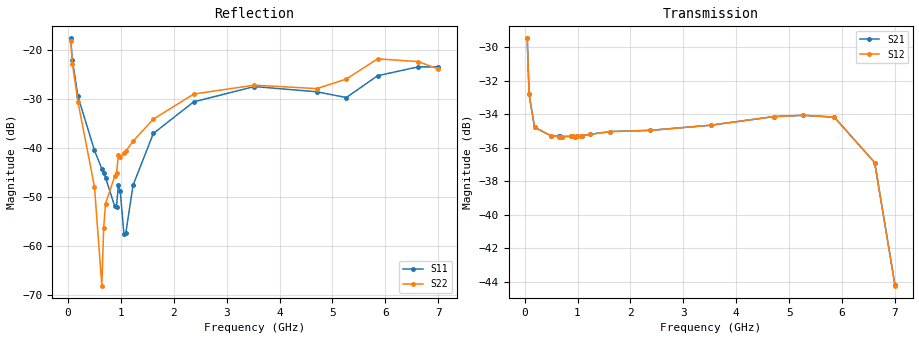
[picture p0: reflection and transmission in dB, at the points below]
! Integrated Device Technology
! Corporate Headquarters
! 6024 Silver Creek Valley Road
! San Jose, CA 95138  USA
! Phone:  1-408-284-8200
! Toll Free:  1-800-223-1366
! Webpage:  http://www.idt.com/
! Timing and RF Division
! 515 Groton Road, Suite 102
! Westford, MA 01886-6024
! Device:  F2258
! Description: Voltage Variable RF Attenuator
! Frequency:  50.0 -  6000.00 MHz
! Package:  3x3 mm Thin QFN Plastic Package: 16 pin
! Ports:  2 RF, 2 DC
!  Pin  1  = NC
!  Pin  2  = NC
!  Pin  3  = RF2  = Port 2
!  Pin  4  = GND
!  Pin  5  = Vdd
!  Pin  6  = NC
!  Pin  7  = VCTRL
!  Pin  8  = NC
!  Pin  9  = GND
!  Pin 10  = RF1  = Port 1
!  Pin 11  = NC
!  Pin 12  = NC
!  Pin 13  = NC
!  Pin 14  = NC
!  Pin 15  = NC
!  Pin 16  = NC
! Vcntrl:  2.170 Volts
! Vdd:  +3.300 Volts
! Current:  1.153 mA
! Data:  The device was measured on a the F2258 evaluation board which has
!  individual transmission lines to the RF pins.  Data was collected
!  using a calibrated network analyzer.  The evaluation board was
!  de-embedded using a TRL calibration technique.
!  The reference plane is the edge of the package pin.
! Misc:  SN 10
!  Action Tracker AT0285
! Date Measured:  2014-12-10
! Date:  2016-01-13  MJV
! Note:
!  Integrated Device Technology supplies this data as a sample of measured
!  data at the package pin for this product.  Your particular data for this
!  product may vary.
!  Data was taken at 25 degrees C.
!  Integrated Device Technology reserves the right to change this data at anytime.
!Freq_(GHz)  S11M_(dB)  S11P_(deg)  S21M_(dB)  S21P_(deg)  S12M_(dB)  S12P_(deg)  S22M_(dB)  S22P_(deg)
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# GHz S dB R 50
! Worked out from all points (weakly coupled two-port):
!   201 points, 50 MHz to 7 GHz, reference 50 ohm
!   highest |S21| = -29.48 dB at 50 MHz (marker M1); lowest = -44.2 dB at 7 GHz (marker M2)
!   lowest |S11| = -57.5 dB at 1.058 GHz (marker M3), VSWR 1.00, Z = 49.9 + j0.0542 ohm
!   |S11| at or under -10 dB: start of sweep to end of sweep
!   |S22| runs from -68.1 to -18.0 dB; largest |S21 - S12| = 8.3e-05
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0.05  -17.55 -111.0  -29.48 -68.1  -29.48 -68.0  -17.99 -110.7
0.08475  -21.98 -107.4  -32.81 -48.4  -32.81 -48.4  -22.71 -105.8
0.189  -29.42 -109.5  -34.79 -24.5  -34.79 -24.6  -30.52 -104.7
0.50175  -40.48 -121.9  -35.30 -11.2  -35.30 -11.2  -47.92 -108.1
0.64075  -44.24 -128.1  -35.33 -9.7  -35.34 -9.7  -68.15 126.8
0.6755  -45.15 -132.1  -35.33 -9.4  -35.34 -9.5  -56.30 82.5
0.71025  -46.02 -137.9  -35.34 -9.2  -35.34 -9.2  -51.40 93.3
0.884  -51.91 166.2  -35.33 -8.5  -35.33 -8.5  -45.79 90.8
0.91875  -51.95 150.6  -35.33 -8.4  -35.33 -8.4  -45.07 90.2
0.9535  -47.55 -162.3  -35.34 -8.3  -35.34 -8.3  -41.51 107.2
0.98825  -48.70 -174.9  -35.32 -8.2  -35.32 -8.2  -41.82 104.4
1.05775  -57.52 155.9  -35.30 -8.1  -35.30 -8.0  -41.00 88.1
1.0925  -57.47 118.9  -35.29 -8.0  -35.28 -8.0  -40.61 84.5
1.2315  -47.58 47.3  -35.21 -8.0  -35.21 -8.0  -38.59 65.1
1.61375  -37.01 32.9  -35.04 -9.7  -35.05 -9.7  -34.08 45.0
2.37825  -30.53 48.2  -34.97 -13.4  -34.97 -13.4  -28.94 38.9
3.525  -27.41 91.6  -34.66 -19.9  -34.66 -19.9  -27.12 64.3
4.7065  -28.48 95.6  -34.15 -29.1  -34.15 -29.0  -27.83 55.7
5.2625  -29.66 54.3  -34.07 -35.2  -34.07 -35.1  -25.87 18.3
5.85325  -25.19 29.9  -34.18 -45.7  -34.18 -45.7  -21.74 -4.4
6.61775  -23.39 49.7  -36.89 -68.7  -36.91 -68.7  -22.30 -45.9
7  -23.37 84.5  -44.19 -61.8  -44.24 -61.5  -23.81 -129.5
